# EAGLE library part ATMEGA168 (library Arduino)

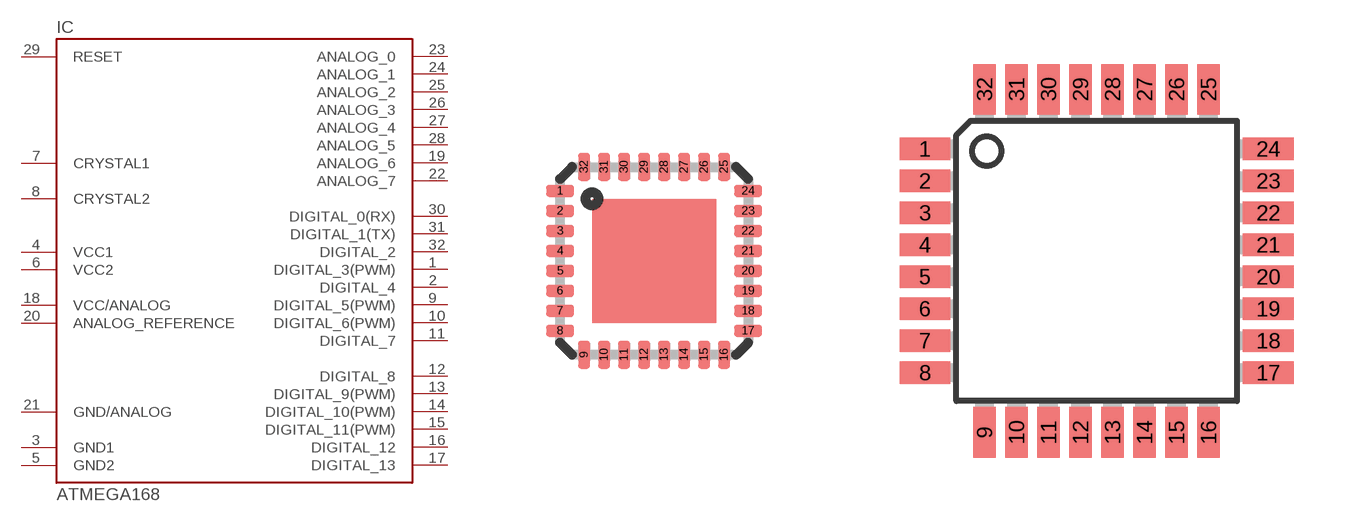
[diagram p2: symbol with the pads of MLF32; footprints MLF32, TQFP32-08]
Designator prefix IC

## ATMEGA168-MU  [MLF32]
1  DIGITAL_3(PWM)
2  DIGITAL_4
3  GND1  pwr
4  VCC1  pwr
5  GND2  pwr
6  VCC2  pwr
7  CRYSTAL1
8  CRYSTAL2
9  DIGITAL_5(PWM)
10  DIGITAL_6(PWM)
11  DIGITAL_7
12  DIGITAL_8
13  DIGITAL_9(PWM)
14  DIGITAL_10(PWM)
15  DIGITAL_11(PWM)
16  DIGITAL_12
17  DIGITAL_13
18  VCC/ANALOG  pas
19  ANALOG_6  pas
20  ANALOG_REFERENCE  pas
21  GND/ANALOG  pwr
22  ANALOG_7  pas
23  ANALOG_0
24  ANALOG_1
25  ANALOG_2
26  ANALOG_3
27  ANALOG_4
28  ANALOG_5
29  RESET
30  DIGITAL_0(RX)
31  DIGITAL_1(TX)
32  DIGITAL_2

## ATMEGA168-AU  [TQFP32-08]
Pads as for MLF32

## Footprint MLF32 (pad centres in mm)
32M1-A Micro Lead Frame package (MLF)
smd 0.7 x 0.3: 1 -2.35,1.75; 2 -2.35,1.25; 3 -2.35,0.75; 4 -2.35,0.25; 5 -2.35,-0.25; 6 -2.35,-0.75; 7 -2.35,-1.25; 8 -2.35,-1.75; 17 2.35,-1.75; 18 2.35,-1.25; 19 2.35,-0.75; 20 2.35,-0.25; 21 2.35,0.25; 22 2.35,0.75; 23 2.35,1.25; 24 2.35,1.75
smd 0.3 x 0.7: 9 -1.75,-2.35; 10 -1.25,-2.35; 11 -0.75,-2.35; 12 -0.25,-2.35; 13 0.25,-2.35; 14 0.75,-2.35; 15 1.25,-2.35; 16 1.75,-2.35; 25 1.75,2.35; 26 1.25,2.35; 27 0.75,2.35; 28 0.25,2.35; 29 -0.25,2.35; 30 -0.75,2.35; 31 -1.25,2.35; 32 -1.75,2.35

## Footprint TQFP32-08 (pad centres in mm)
Thin Plasic Quad Flat Package Grid 0.8 mm
smd 1.27 x 0.559: 1 -4.293,2.8; 2 -4.293,2; 3 -4.293,1.2; 4 -4.293,0.4; 5 -4.293,-0.4; 6 -4.293,-1.2; 7 -4.293,-2; 8 -4.293,-2.8; 17 4.293,-2.8; 18 4.293,-2; 19 4.293,-1.2; 20 4.293,-0.4; 21 4.293,0.4; 22 4.293,1.2; 23 4.293,2; 24 4.293,2.8
smd 0.559 x 1.27: 9 -2.8,-4.293; 10 -2,-4.293; 11 -1.2,-4.293; 12 -0.4,-4.293; 13 0.4,-4.293; 14 1.2,-4.293; 15 2,-4.293; 16 2.8,-4.293; 25 2.8,4.293; 26 2,4.293; 27 1.2,4.293; 28 0.4,4.293; 29 -0.4,4.293; 30 -1.2,4.293; 31 -2,4.293; 32 -2.8,4.293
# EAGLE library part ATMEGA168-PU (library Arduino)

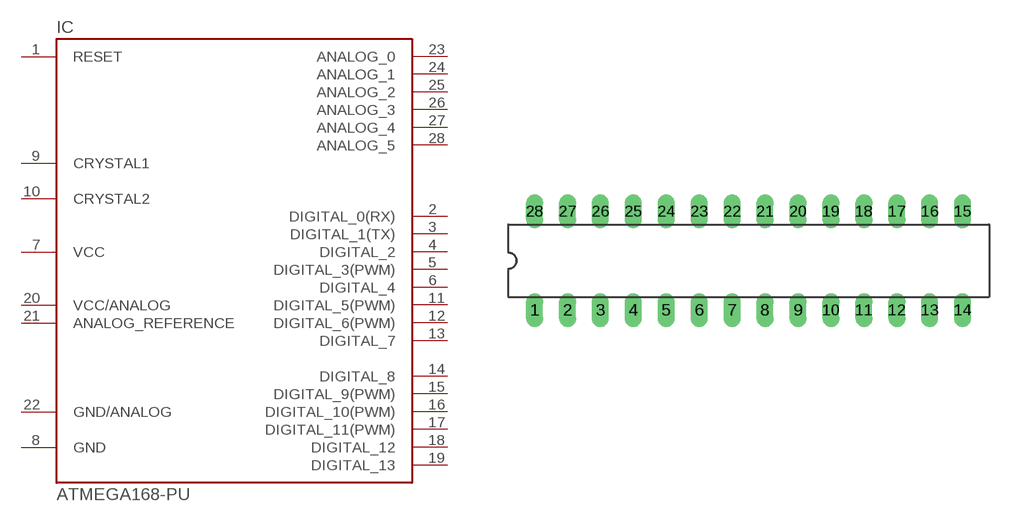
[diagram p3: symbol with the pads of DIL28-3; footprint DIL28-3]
Designator prefix IC

## ATMEGA168-PU  [DIL28-3]
1  RESET
2  DIGITAL_0(RX)
3  DIGITAL_1(TX)
4  DIGITAL_2
5  DIGITAL_3(PWM)
6  DIGITAL_4
7  VCC  pwr
8  GND  pwr
9  CRYSTAL1
10  CRYSTAL2
11  DIGITAL_5(PWM)
12  DIGITAL_6(PWM)
13  DIGITAL_7
14  DIGITAL_8
15  DIGITAL_9(PWM)
16  DIGITAL_10(PWM)
17  DIGITAL_11(PWM)
18  DIGITAL_12
19  DIGITAL_13
20  VCC/ANALOG  pas
21  ANALOG_REFERENCE  pas
22  GND/ANALOG  pwr
23  ANALOG_0
24  ANALOG_1
25  ANALOG_2
26  ANALOG_3
27  ANALOG_4
28  ANALOG_5

## Footprint DIL28-3 (pad centres in mm)
Dual In Line 0.3 inch
drill 0.813 long: 1 -16.51,-3.81; 2 -13.97,-3.81; 3 -11.43,-3.81; 4 -8.89,-3.81; 5 -6.35,-3.81; 6 -3.81,-3.81; 7 -1.27,-3.81; 8 1.27,-3.81; 9 3.81,-3.81; 10 6.35,-3.81; 11 8.89,-3.81; 12 11.43,-3.81; 13 13.97,-3.81; 14 16.51,-3.81; 15 16.51,3.81; 16 13.97,3.81; 17 11.43,3.81; 18 8.89,3.81; 19 6.35,3.81; 20 3.81,3.81; 21 1.27,3.81; 22 -1.27,3.81; 23 -3.81,3.81; 24 -6.35,3.81; 25 -8.89,3.81; 26 -11.43,3.81; 27 -13.97,3.81; 28 -16.51,3.81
